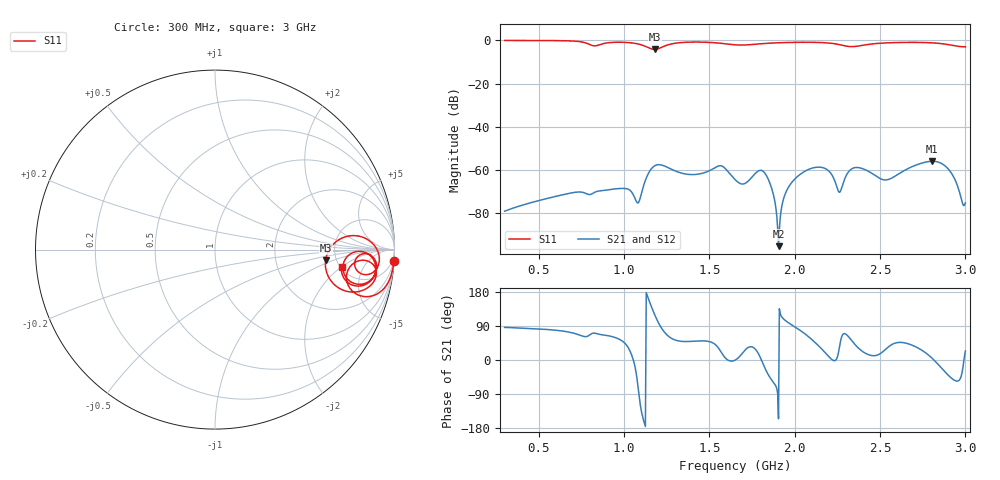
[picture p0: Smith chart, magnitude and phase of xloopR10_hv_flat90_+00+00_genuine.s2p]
! xloopR10_hv_flat90_+00+00_genuine, gap C 0.80 pF
! simulated by sim/fixtures_fdtd.py (S12 = S21, S22 not computed)
# HZ S RI R 50
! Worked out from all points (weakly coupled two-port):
!   541 points, 300 MHz to 3 GHz, reference 50 ohm
!   highest |S21| = -55.96 dB at 2.805 GHz (marker M1); lowest = -95.3 dB at 1.905 GHz (marker M2)
!   lowest |S11| = -4.2 dB at 1.18 GHz (marker M3), VSWR 4.25, Z = 204 - j39.3 ohm
!   |S11| at or under -10 dB: nowhere
!   |S22| runs from - to - dB; largest |S21 - S12| = 0
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3e8  0.9972 -0.0608  7.8e-06 0.000111  7.8e-06 0.000111  0 0
7.5e8  0.8911 -0.2527  0.000134 0.000277  0.000134 0.000277  0 0
8.65e8  0.8134 -0.0599  0.00013 0.000304  0.00013 0.000304  0 0
1.01e9  0.8814 -0.1829  0.000277 0.000247  0.000277 0.000247  0 0
1.08e9  0.7988 -0.234  7.36e-05 -0.000155  7.36e-05 -0.000155  0 0
1.18e9  0.6161 -0.0593  -0.000607 0.0011  -0.000607 0.0011  0 0
1.2e9  0.6422 0.00938  -0.000221 0.00131  -0.000221 0.00131  0 0
1.395e9  0.915 -0.0395  0.000511 0.000593  0.000511 0.000593  0 0
1.57e9  0.8452 -0.1396  0.00117 0.000429  0.00117 0.000429  0 0
1.65e9  0.7854 -0.1078  0.000601 -5.7e-06  0.000601 -5.7e-06  0 0
1.7e9  0.7804 -0.0637  0.000442 0.000176  0.000442 0.000176  0 0
1.815e9  0.8446 -0.023  0.000914 -0.000173  0.000914 -0.000173  0 0
1.905e9  0.8829 -0.0449  -1.56e-05 -7.3e-06  -1.56e-05 -7.3e-06  0 0
1.98e9  0.8978 -0.0731  -2.87e-05 0.000499  -2.87e-05 0.000499  0 0
2.1e9  0.8961 -0.1276  0.000645 0.000891  0.000645 0.000891  0 0
2.195e9  0.8553 -0.1791  0.000966 0.000192  0.000966 0.000192  0 0
2.26e9  0.7798 -0.1897  0.000268 0.000146  0.000268 0.000146  0 0
2.35e9  0.7214 -0.0619  0.000833 0.000764  0.000833 0.000764  0 0
2.55e9  0.8806 -0.0515  0.000496 0.000347  0.000496 0.000347  0 0
2.805e9  0.8607 -0.18  0.00159 0.000129  0.00159 0.000129  0 0
2.905e9  0.7689 -0.1988  0.000732 -0.000672  0.000732 -0.000672  0 0
3e9  0.7059 -0.0954  0.000158 6.97e-05  0.000158 6.97e-05  0 0
